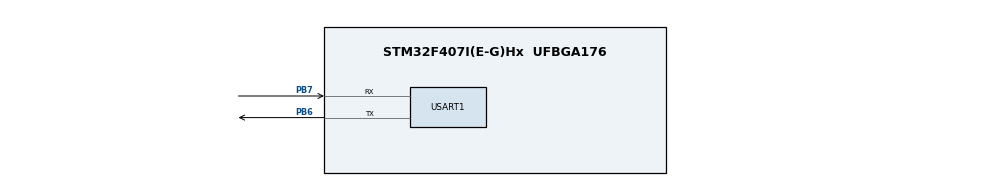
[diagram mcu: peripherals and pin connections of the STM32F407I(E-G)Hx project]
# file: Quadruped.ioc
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Dma.Request0=USART1_RX
Dma.Request1=USART1_TX
Dma.USART1_RX.0.Direction=DMA_PERIPH_TO_MEMORY
Dma.USART1_RX.0.FIFOMode=DMA_FIFOMODE_DISABLE
Dma.USART1_RX.0.Instance=DMA2_Stream2
Dma.USART1_RX.0.MemDataAlignment=DMA_MDATAALIGN_BYTE
Dma.USART1_RX.0.MemInc=DMA_MINC_ENABLE
Dma.USART1_RX.0.Mode=DMA_NORMAL
Dma.USART1_RX.0.PeriphDataAlignment=DMA_PDATAALIGN_BYTE
Dma.USART1_RX.0.PeriphInc=DMA_PINC_DISABLE
Dma.USART1_RX.0.Priority=DMA_PRIORITY_LOW
Dma.USART1_TX.1.Direction=DMA_MEMORY_TO_PERIPH
Dma.USART1_TX.1.FIFOMode=DMA_FIFOMODE_DISABLE
Dma.USART1_TX.1.Instance=DMA2_Stream7
Dma.USART1_TX.1.MemDataAlignment=DMA_MDATAALIGN_BYTE
Dma.USART1_TX.1.MemInc=DMA_MINC_ENABLE
Dma.USART1_TX.1.Mode=DMA_NORMAL
Dma.USART1_TX.1.PeriphDataAlignment=DMA_PDATAALIGN_BYTE
Dma.USART1_TX.1.PeriphInc=DMA_PINC_DISABLE
Dma.USART1_TX.1.Priority=DMA_PRIORITY_LOW
Mcu.Family=STM32F4
Mcu.Name=STM32F407I(E-G)Hx
Mcu.Package=UFBGA176
NVIC.DMA2_Stream2_IRQn=true\:0\:0\:false\:false\:true\:false\:true\:true
NVIC.DMA2_Stream7_IRQn=true\:0\:0\:false\:false\:true\:false\:true\:true
NVIC.PriorityGroup=NVIC_PRIORITYGROUP_4
NVIC.USART1_IRQn=true\:0\:0\:false\:false\:true\:false\:true\:true
PA13.Mode=Serial_Wire
PA13.Signal=SYS_JTMS-SWDIO
PA14.Mode=Serial_Wire
PA14.Signal=SYS_JTCK-SWCLK
PB6.Mode=Asynchronous
PB6.Signal=USART1_TX
PB7.Mode=Asynchronous
PB7.Signal=USART1_RX
ProjectManager.HeapSize=0x200
ProjectManager.StackSize=0x400
ProjectManager.TargetToolchain=MDK-ARM V5.32
RCC.48MHZClocksFreq_Value=84000000
RCC.AHBFreq_Value=168000000
RCC.APB1CLKDivider=RCC_HCLK_DIV4
RCC.APB1Freq_Value=42000000
RCC.APB1TimFreq_Value=84000000
RCC.APB2CLKDivider=RCC_HCLK_DIV2
RCC.APB2Freq_Value=84000000
RCC.APB2TimFreq_Value=168000000
RCC.CortexFreq_Value=168000000
RCC.HCLKFreq_Value=168000000
RCC.HSE_VALUE=25000000
RCC.HSI_VALUE=16000000
RCC.LSE_VALUE=32768
RCC.PLLM=8
RCC.PLLN=168
RCC.SYSCLKFreq_VALUE=168000000
RCC.SYSCLKSource=RCC_SYSCLKSOURCE_PLLCLK
RCC.VCOOutputFreq_Value=336000000
USART1.VirtualMode=VM_ASYNC
board=custom

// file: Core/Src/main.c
/* USER CODE BEGIN Header */
/**
  ******************************************************************************
  * @file           : main.c
  * @brief          : Main program body
  ******************************************************************************
  * @attention
  *
  * Copyright (c) 2026 STMicroelectronics.
  * All rights reserved.
  *
  * This software is licensed under terms that can be found in the LICENSE file
  * in the root directory of this software component.
  * If no LICENSE file comes with this software, it is provided AS-IS.
  *
  ******************************************************************************
  */
/* USER CODE END Header */
#include "main.h"

/* USER CODE BEGIN Includes */
#include "servo.h"
#include "pp_kinematics.h"
#include "ypp_kinematics.h"
/* USER CODE END Includes */

UART_HandleTypeDef huart1;
DMA_HandleTypeDef hdma_usart1_rx;
DMA_HandleTypeDef hdma_usart1_tx;

void SystemClock_Config(void);
static void MX_GPIO_Init(void);
static void MX_DMA_Init(void);
static void MX_USART1_UART_Init(void);

int main(void)
{

  /* USER CODE BEGIN 1 */
    MX_USART1_UART_Init();
    Servo_Init(&huart1);    // 绑定舵机到 UART1
  /* USER CODE END 1 */

  /* MCU Configuration--------------------------------------------------------*/

  /* Reset of all peripherals, Initializes the Flash interface and the Systick. */
  HAL_Init();

  /* Configure the system clock */
  SystemClock_Config();

  /* Initialize all configured peripherals */
  MX_GPIO_Init();
  MX_DMA_Init();
  MX_USART1_UART_Init();

  /* Infinite loop */
  while (1)
  {

  }
}

void SystemClock_Config(void)
{
  RCC_OscInitTypeDef RCC_OscInitStruct = {0};
  RCC_ClkInitTypeDef RCC_ClkInitStruct = {0};

  /** Configure the main internal regulator output voltage
  */
  __HAL_RCC_PWR_CLK_ENABLE();
  __HAL_PWR_VOLTAGESCALING_CONFIG(PWR_REGULATOR_VOLTAGE_SCALE1);

  /** Initializes the RCC Oscillators according to the specified parameters
  * in the RCC_OscInitTypeDef structure.
  */
  RCC_OscInitStruct.OscillatorType = RCC_OSCILLATORTYPE_HSI;
  RCC_OscInitStruct.HSIState = RCC_HSI_ON;
  RCC_OscInitStruct.HSICalibrationValue = RCC_HSICALIBRATION_DEFAULT;
  RCC_OscInitStruct.PLL.PLLState = RCC_PLL_NONE;
  if (HAL_RCC_OscConfig(&RCC_OscInitStruct) != HAL_OK)
  {
    Error_Handler();
  }

  /** Initializes the CPU, AHB and APB buses clocks
  */
  RCC_ClkInitStruct.ClockType = RCC_CLOCKTYPE_HCLK|RCC_CLOCKTYPE_SYSCLK
                              |RCC_CLOCKTYPE_PCLK1|RCC_CLOCKTYPE_PCLK2;
  RCC_ClkInitStruct.SYSCLKSource = RCC_SYSCLKSOURCE_HSI;
  RCC_ClkInitStruct.AHBCLKDivider = RCC_SYSCLK_DIV1;
  RCC_ClkInitStruct.APB1CLKDivider = RCC_HCLK_DIV1;
  RCC_ClkInitStruct.APB2CLKDivider = RCC_HCLK_DIV1;

  if (HAL_RCC_ClockConfig(&RCC_ClkInitStruct, FLASH_LATENCY_0) != HAL_OK)
  {
    Error_Handler();
  }
}

static void MX_USART1_UART_Init(void)
{

  huart1.Instance = USART1;
  huart1.Init.BaudRate = 115200;
  huart1.Init.WordLength = UART_WORDLENGTH_8B;
  huart1.Init.StopBits = UART_STOPBITS_1;
  huart1.Init.Parity = UART_PARITY_NONE;
  huart1.Init.Mode = UART_MODE_TX_RX;
  huart1.Init.HwFlowCtl = UART_HWCONTROL_NONE;
  huart1.Init.OverSampling = UART_OVERSAMPLING_16;
  if (HAL_UART_Init(&huart1) != HAL_OK)
  {
    Error_Handler();
  }

}

static void MX_DMA_Init(void)
{

  /* DMA controller clock enable */
  __HAL_RCC_DMA2_CLK_ENABLE();

  /* DMA interrupt init */
  /* DMA2_Stream2_IRQn interrupt configuration */
  HAL_NVIC_SetPriority(DMA2_Stream2_IRQn, 0, 0);
  HAL_NVIC_EnableIRQ(DMA2_Stream2_IRQn);
  /* DMA2_Stream7_IRQn interrupt configuration */
  HAL_NVIC_SetPriority(DMA2_Stream7_IRQn, 0, 0);
  HAL_NVIC_EnableIRQ(DMA2_Stream7_IRQn);

}

static void MX_GPIO_Init(void)
{

  /* GPIO Ports Clock Enable */
  __HAL_RCC_GPIOA_CLK_ENABLE();
  __HAL_RCC_GPIOB_CLK_ENABLE();

}

void Error_Handler(void)
{
  __disable_irq();
  while (1)
  {
  }
}
